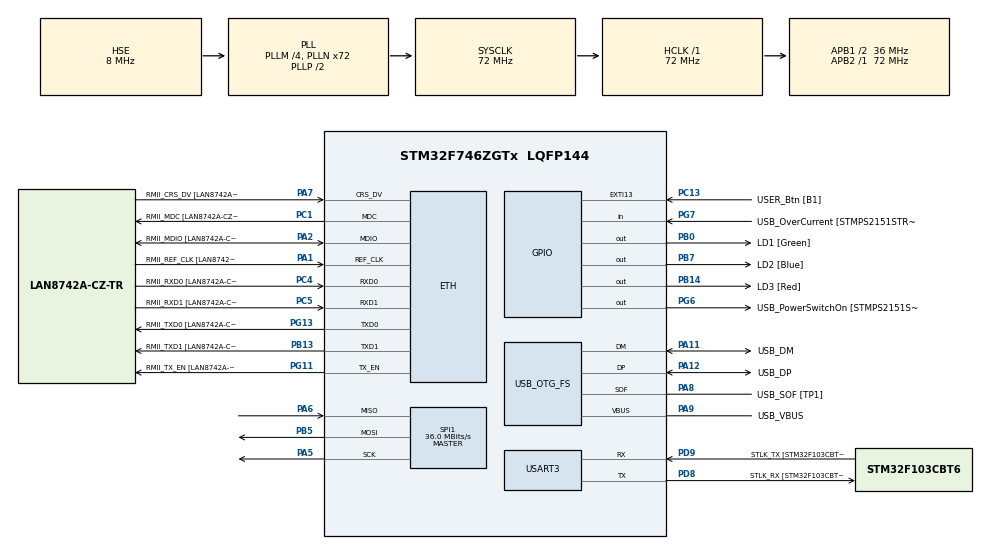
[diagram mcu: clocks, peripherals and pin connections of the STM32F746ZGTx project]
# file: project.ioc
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ETH.MediaInterface=ETH_MEDIA_INTERFACE_RMII
ETH.PHY_Name=LAN8742A_PHY_ADDRESS
ETH.PHY_Value=0
ETH.PhyAddress=0
FREERTOS.Tasks01=defaultTask,0,128,StartDefaultTask,Default,NULL
LWIP.Version=v2.0.3_Cube
Mcu.Family=STM32F7
Mcu.Name=STM32F746ZGTx
Mcu.Package=LQFP144
NVIC.ETH_IRQn=true\:5\:0\:false\:false\:true\:true\:false
NVIC.PriorityGroup=NVIC_PRIORITYGROUP_4
NVIC.TIM1_UP_TIM10_IRQn=true\:0\:0\:false\:false\:true\:false\:false
NVIC.TimeBase=TIM1_UP_TIM10_IRQn
NVIC.TimeBaseIP=TIM1
PA1.GPIO_Label=RMII_REF_CLK [LAN8742A-CZ-TR_REFCLK0]
PA1.Mode=RMII
PA1.Signal=ETH_REF_CLK
PA10.GPIO_Label=USB_ID
PA10.Signal=USB_OTG_FS_ID
PA11.GPIO_Label=USB_DM
PA11.Mode=Device_Only
PA11.Signal=USB_OTG_FS_DM
PA12.GPIO_Label=USB_DP
PA12.Mode=Device_Only
PA12.Signal=USB_OTG_FS_DP
PA13.GPIO_Label=TMS
PA13.Mode=Serial_Wire
PA13.Signal=SYS_JTMS-SWDIO
PA14.GPIO_Label=TCK
PA14.Mode=Serial_Wire
PA14.Signal=SYS_JTCK-SWCLK
PA2.GPIO_Label=RMII_MDIO [LAN8742A-CZ-TR_MDIO]
PA2.Mode=RMII
PA2.Signal=ETH_MDIO
PA5.Mode=Full_Duplex_Master
PA5.Signal=SPI1_SCK
PA6.Mode=Full_Duplex_Master
PA6.Signal=SPI1_MISO
PA7.GPIO_Label=RMII_CRS_DV [LAN8742A-CZ-TR_CRS_DV]
PA7.Mode=RMII
PA7.Signal=ETH_CRS_DV
PA8.GPIO_Label=USB_SOF [TP1]
PA8.Mode=Activate_SOF_FS
PA8.Signal=USB_OTG_FS_SOF
PA9.GPIO_Label=USB_VBUS
PA9.Mode=Activate_VBUS
PA9.Signal=USB_OTG_FS_VBUS
PB0.GPIO_Label=LD1 [Green]
PB0.Signal=GPIO_Output
PB13.GPIO_Label=RMII_TXD1 [LAN8742A-CZ-TR_TXD1]
PB13.Mode=RMII
PB13.Signal=ETH_TXD1
PB14.GPIO_Label=LD3 [Red]
PB14.Signal=GPIO_Output
PB3.GPIO_Label=SW0
PB3.Signal=SYS_JTDO-SWO
PB5.Mode=Full_Duplex_Master
PB5.Signal=SPI1_MOSI
PB7.GPIO_Label=LD2 [Blue]
PB7.Signal=GPIO_Output
PC1.GPIO_Label=RMII_MDC [LAN8742A-CZ-TR_MDC]
PC1.Mode=RMII
PC1.Signal=ETH_MDC
PC13.GPIO_Label=USER_Btn [B1]
PC13.Signal=GPXTI13
PC14/OSC32_IN.Mode=LSE-External-Oscillator
PC14/OSC32_IN.Signal=RCC_OSC32_IN
PC15/OSC32_OUT.Mode=LSE-External-Oscillator
PC15/OSC32_OUT.Signal=RCC_OSC32_OUT
PC4.GPIO_Label=RMII_RXD0 [LAN8742A-CZ-TR_RXD0]
PC4.Mode=RMII
PC4.Signal=ETH_RXD0
PC5.GPIO_Label=RMII_RXD1 [LAN8742A-CZ-TR_RXD1]
PC5.Mode=RMII
PC5.Signal=ETH_RXD1
PD8.GPIO_Label=STLK_RX [STM32F103CBT6_PA3]
PD8.Mode=Asynchronous
PD8.Signal=USART3_TX
PD9.GPIO_Label=STLK_TX [STM32F103CBT6_PA2]
PD9.Mode=Asynchronous
PD9.Signal=USART3_RX
PG11.GPIO_Label=RMII_TX_EN [LAN8742A-CZ-TR_TXEN]
PG11.Mode=RMII
PG11.Signal=ETH_TX_EN
PG13.GPIO_Label=RMII_TXD0 [LAN8742A-CZ-TR_TXD0]
PG13.Mode=RMII
PG13.Signal=ETH_TXD0
PG6.GPIO_Label=USB_PowerSwitchOn [STMPS2151STR_EN]
PG6.Signal=GPIO_Output
PG7.GPIO_Label=USB_OverCurrent [STMPS2151STR_FAULT]
PG7.Signal=GPIO_Input
PH0/OSC_IN.GPIO_Label=MCO [STM32F103CBT6_PA8]
PH0/OSC_IN.Mode=HSE-External-Clock-Source
PH0/OSC_IN.Signal=RCC_OSC_IN
PH1/OSC_OUT.Mode=HSE-External-Clock-Source
PH1/OSC_OUT.Signal=RCC_OSC_OUT
ProjectManager.HeapSize=0x200
ProjectManager.StackSize=0x400
ProjectManager.TargetToolchain=TrueSTUDIO
RCC.48MHZClocksFreq_Value=24000000
RCC.AHBFreq_Value=72000000
RCC.APB1CLKDivider=RCC_HCLK_DIV2
RCC.APB1Freq_Value=36000000
RCC.APB1TimFreq_Value=72000000
RCC.APB2Freq_Value=72000000
RCC.APB2TimFreq_Value=72000000
RCC.CortexFreq_Value=72000000
RCC.HCLKFreq_Value=72000000
RCC.HSE_VALUE=8000000
RCC.HSI_VALUE=16000000
RCC.PLLM=4
RCC.PLLMUL=RCC_PLL_MUL9
RCC.PLLN=72
RCC.PLLQ=3
RCC.PRESCALERUSB=RCC_USBCLKSOURCE_PLL_DIV1_5
RCC.SYSCLKFreq_VALUE=72000000
RCC.SYSCLKSource=RCC_SYSCLKSOURCE_PLLCLK
RCC.SYSCLKSourceVirtual=RCC_SYSCLKSOURCE_PLLCLK
RCC.USBFreq_Value=48000000
RCC.VCOOutputFreq_Value=144000000
SPI1.CalculateBaudRate=36.0 MBits/s
SPI1.Direction=SPI_DIRECTION_2LINES
SPI1.Mode=SPI_MODE_MASTER
SPI1.VirtualType=VM_MASTER
USART3.VirtualMode-Asynchronous=VM_ASYNC
USB_OTG_FS.VirtualMode=Device_Only
VP_FREERTOS_VS_ENABLE.Mode=Enabled
VP_LWIP_VS_Enabled.Mode=Enabled
VP_SYS_VS_tim1.Mode=TIM1
board=NUCLEO-F746ZG

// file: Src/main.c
/**
  ******************************************************************************
  * @file           : main.c
  * @brief          : Main program body
  ******************************************************************************
  * This notice applies to any and all portions of this file
  * that are not between comment pairs USER CODE BEGIN and
  * USER CODE END. Other portions of this file, whether
  * inserted by the user or by software development tools
  * are owned by their respective copyright owners.
  *
  * Copyright (c) 2018 STMicroelectronics International N.V.
  * All rights reserved.
  *
  * Redistribution and use in source and binary forms, with or without
  * modification, are permitted, provided that the following conditions are met:
  *
  * 1. Redistribution of source code must retain the above copyright notice,
  *    this list of conditions and the following disclaimer.
  * 2. Redistributions in binary form must reproduce the above copyright notice,
  *    this list of conditions and the following disclaimer in the documentation
  *    and/or other materials provided with the distribution.
  * 3. Neither the name of STMicroelectronics nor the names of other
  *    contributors to this software may be used to endorse or promote products
  *    derived from this software without specific written permission.
  * 4. This software, including modifications and/or derivative works of this
  *    software, must execute solely and exclusively on microcontroller or
  *    microprocessor devices manufactured by or for STMicroelectronics.
  * 5. Redistribution and use of this software other than as permitted under
  *    this license is void and will automatically terminate your rights under
  *    this license.
  *
  * THIS SOFTWARE IS PROVIDED BY STMICROELECTRONICS AND CONTRIBUTORS "AS IS"
  * AND ANY EXPRESS, IMPLIED OR STATUTORY WARRANTIES, INCLUDING, BUT NOT
  * LIMITED TO, THE IMPLIED WARRANTIES OF MERCHANTABILITY, FITNESS FOR A
  * PARTICULAR PURPOSE AND NON-INFRINGEMENT OF THIRD PARTY INTELLECTUAL PROPERTY
  * RIGHTS ARE DISCLAIMED TO THE FULLEST EXTENT PERMITTED BY LAW. IN NO EVENT
  * SHALL STMICROELECTRONICS OR CONTRIBUTORS BE LIABLE FOR ANY DIRECT, INDIRECT,
  * INCIDENTAL, SPECIAL, EXEMPLARY, OR CONSEQUENTIAL DAMAGES (INCLUDING, BUT NOT
  * LIMITED TO, PROCUREMENT OF SUBSTITUTE GOODS OR SERVICES; LOSS OF USE, DATA,
  * OR PROFITS; OR BUSINESS INTERRUPTION) HOWEVER CAUSED AND ON ANY THEORY OF
  * LIABILITY, WHETHER IN CONTRACT, STRICT LIABILITY, OR TORT (INCLUDING
  * NEGLIGENCE OR OTHERWISE) ARISING IN ANY WAY OUT OF THE USE OF THIS SOFTWARE,
  * EVEN IF ADVISED OF THE POSSIBILITY OF SUCH DAMAGE.
  *
  ******************************************************************************
  */
#include "main.h"
#include "stm32f7xx_hal.h"
#include "cmsis_os.h"
#include "lwip.h"

/* USER CODE BEGIN Includes */

#include "rfid-rc522.h"
#include "term_io.h"
#include "httpserver-netconn.h"
#include "tag_scanner.h"

/* USER CODE END Includes */

SPI_HandleTypeDef hspi1;
UART_HandleTypeDef huart3;
PCD_HandleTypeDef hpcd_USB_OTG_FS;
osThreadId defaultTaskHandle;

/* USER CODE BEGIN PV */
/* Private variables ---------------------------------------------------------*/
extern struct netif gnetif;
int privilage_status = 2;
int add_admin = 0;

/* USER CODE END PV */

void SystemClock_Config(void);
static void MX_GPIO_Init(void);
static void MX_USB_OTG_FS_PCD_Init(void);
static void MX_SPI1_Init(void);
static void MX_USART3_UART_Init(void);
void StartDefaultTask(void const * argument);

/* USER CODE BEGIN PFP */
/* Private function prototypes -----------------------------------------------*/

/* USER CODE END PFP */

int main(void)
{

  /* MCU Configuration----------------------------------------------------------*/

  /* Reset of all peripherals, Initializes the Flash interface and the Systick. */
  HAL_Init();

  /* Configure the system clock */
  SystemClock_Config();

  /* Initialize all configured peripherals */
  MX_GPIO_Init();
  MX_USB_OTG_FS_PCD_Init();
  MX_SPI1_Init();
  MX_USART3_UART_Init();

  /* USER CODE BEGIN 2 */
  RFID_RC522_Init();
  debug_init(&huart3);

  /* USER CODE END 2 */

  /* Create the thread(s) */
  /* definition and creation of defaultTask */
  osThreadDef(defaultTask, StartDefaultTask, osPriorityNormal, 0, 128);
  defaultTaskHandle = osThreadCreate(osThread(defaultTask), NULL);

  /* Start scheduler */
  osKernelStart();

  /* We should never get here as control is now taken by the scheduler */

  /* Infinite loop */
  while (1)
  {

  }

}

void SystemClock_Config(void)
{

  RCC_OscInitTypeDef RCC_OscInitStruct;
  RCC_ClkInitTypeDef RCC_ClkInitStruct;
  RCC_PeriphCLKInitTypeDef PeriphClkInitStruct;

    /**Configure the main internal regulator output voltage
    */
  __HAL_RCC_PWR_CLK_ENABLE();

  __HAL_PWR_VOLTAGESCALING_CONFIG(PWR_REGULATOR_VOLTAGE_SCALE3);

    /**Initializes the CPU, AHB and APB busses clocks
    */
  RCC_OscInitStruct.OscillatorType = RCC_OSCILLATORTYPE_HSE;
  RCC_OscInitStruct.HSEState = RCC_HSE_BYPASS;
  RCC_OscInitStruct.PLL.PLLState = RCC_PLL_ON;
  RCC_OscInitStruct.PLL.PLLSource = RCC_PLLSOURCE_HSE;
  RCC_OscInitStruct.PLL.PLLM = 4;
  RCC_OscInitStruct.PLL.PLLN = 72;
  RCC_OscInitStruct.PLL.PLLP = RCC_PLLP_DIV2;
  RCC_OscInitStruct.PLL.PLLQ = 3;
  if (HAL_RCC_OscConfig(&RCC_OscInitStruct) != HAL_OK)
  {
    _Error_Handler(__FILE__, __LINE__);
  }

    /**Initializes the CPU, AHB and APB busses clocks
    */
  RCC_ClkInitStruct.ClockType = RCC_CLOCKTYPE_HCLK|RCC_CLOCKTYPE_SYSCLK
                              |RCC_CLOCKTYPE_PCLK1|RCC_CLOCKTYPE_PCLK2;
  RCC_ClkInitStruct.SYSCLKSource = RCC_SYSCLKSOURCE_PLLCLK;
  RCC_ClkInitStruct.AHBCLKDivider = RCC_SYSCLK_DIV1;
  RCC_ClkInitStruct.APB1CLKDivider = RCC_HCLK_DIV2;
  RCC_ClkInitStruct.APB2CLKDivider = RCC_HCLK_DIV1;

  if (HAL_RCC_ClockConfig(&RCC_ClkInitStruct, FLASH_LATENCY_2) != HAL_OK)
  {
    _Error_Handler(__FILE__, __LINE__);
  }

  PeriphClkInitStruct.PeriphClockSelection = RCC_PERIPHCLK_USART3|RCC_PERIPHCLK_CLK48;
  PeriphClkInitStruct.Usart3ClockSelection = RCC_USART3CLKSOURCE_PCLK1;
  PeriphClkInitStruct.Clk48ClockSelection = RCC_CLK48SOURCE_PLL;
  if (HAL_RCCEx_PeriphCLKConfig(&PeriphClkInitStruct) != HAL_OK)
  {
    _Error_Handler(__FILE__, __LINE__);
  }

    /**Configure the Systick interrupt time
    */
  HAL_SYSTICK_Config(HAL_RCC_GetHCLKFreq()/1000);

    /**Configure the Systick
    */
  HAL_SYSTICK_CLKSourceConfig(SYSTICK_CLKSOURCE_HCLK);

  /* SysTick_IRQn interrupt configuration */
  HAL_NVIC_SetPriority(SysTick_IRQn, 15, 0);
}

/* SPI1 init function */
static void MX_SPI1_Init(void)
{

  /* SPI1 parameter configuration*/
  hspi1.Instance = SPI1;
  hspi1.Init.Mode = SPI_MODE_MASTER;
  hspi1.Init.Direction = SPI_DIRECTION_2LINES;
  hspi1.Init.DataSize = SPI_DATASIZE_8BIT;
  hspi1.Init.CLKPolarity = SPI_POLARITY_LOW;
  hspi1.Init.CLKPhase = SPI_PHASE_1EDGE;
  hspi1.Init.NSS = SPI_NSS_SOFT;
  hspi1.Init.BaudRatePrescaler = SPI_BAUDRATEPRESCALER_32;
  hspi1.Init.FirstBit = SPI_FIRSTBIT_MSB;
  hspi1.Init.TIMode = SPI_TIMODE_DISABLE;
  hspi1.Init.CRCCalculation = SPI_CRCCALCULATION_DISABLE;
  hspi1.Init.CRCPolynomial = 7;
  hspi1.Init.CRCLength = SPI_CRC_LENGTH_DATASIZE;
  hspi1.Init.NSSPMode = SPI_NSS_PULSE_ENABLE;
  if (HAL_SPI_Init(&hspi1) != HAL_OK)
  {
    _Error_Handler(__FILE__, __LINE__);
  }

}

/* USART3 init function */
static void MX_USART3_UART_Init(void)
{

  huart3.Instance = USART3;
  huart3.Init.BaudRate = 115200;
  huart3.Init.WordLength = UART_WORDLENGTH_8B;
  huart3.Init.StopBits = UART_STOPBITS_1;
  huart3.Init.Parity = UART_PARITY_NONE;
  huart3.Init.Mode = UART_MODE_TX_RX;
  huart3.Init.HwFlowCtl = UART_HWCONTROL_NONE;
  huart3.Init.OverSampling = UART_OVERSAMPLING_16;
  huart3.Init.OneBitSampling = UART_ONE_BIT_SAMPLE_DISABLE;
  huart3.AdvancedInit.AdvFeatureInit = UART_ADVFEATURE_NO_INIT;
  if (HAL_UART_Init(&huart3) != HAL_OK)
  {
    _Error_Handler(__FILE__, __LINE__);
  }

}

/* USB_OTG_FS init function */
static void MX_USB_OTG_FS_PCD_Init(void)
{

  hpcd_USB_OTG_FS.Instance = USB_OTG_FS;
  hpcd_USB_OTG_FS.Init.dev_endpoints = 6;
  hpcd_USB_OTG_FS.Init.speed = PCD_SPEED_FULL;
  hpcd_USB_OTG_FS.Init.dma_enable = DISABLE;
  hpcd_USB_OTG_FS.Init.ep0_mps = DEP0CTL_MPS_64;
  hpcd_USB_OTG_FS.Init.phy_itface = PCD_PHY_EMBEDDED;
  hpcd_USB_OTG_FS.Init.Sof_enable = ENABLE;
  hpcd_USB_OTG_FS.Init.low_power_enable = DISABLE;
  hpcd_USB_OTG_FS.Init.lpm_enable = DISABLE;
  hpcd_USB_OTG_FS.Init.vbus_sensing_enable = ENABLE;
  hpcd_USB_OTG_FS.Init.use_dedicated_ep1 = DISABLE;
  if (HAL_PCD_Init(&hpcd_USB_OTG_FS) != HAL_OK)
  {
    _Error_Handler(__FILE__, __LINE__);
  }

}

/** Configure pins as
        * Analog
        * Input
        * Output
        * EVENT_OUT
        * EXTI
*/
static void MX_GPIO_Init(void)
{

  GPIO_InitTypeDef GPIO_InitStruct;

  /* GPIO Ports Clock Enable */
  __HAL_RCC_GPIOC_CLK_ENABLE();
  __HAL_RCC_GPIOH_CLK_ENABLE();
  __HAL_RCC_GPIOA_CLK_ENABLE();
  __HAL_RCC_GPIOB_CLK_ENABLE();
  __HAL_RCC_GPIOD_CLK_ENABLE();
  __HAL_RCC_GPIOG_CLK_ENABLE();

  /*Configure GPIO pin Output Level */
  HAL_GPIO_WritePin(GPIOB, LD1_Pin|LD3_Pin|LD2_Pin, GPIO_PIN_RESET);

  /*Configure GPIO pin Output Level */
  HAL_GPIO_WritePin(GPIOD, GPIO_PIN_9, GPIO_PIN_RESET);

  /*Configure GPIO pin Output Level */
  HAL_GPIO_WritePin(GPIOD, SPI_CS_Pin|RFID_RST_Pin, GPIO_PIN_SET);

  /*Configure GPIO pin Output Level */
  HAL_GPIO_WritePin(USB_PowerSwitchOn_GPIO_Port, USB_PowerSwitchOn_Pin, GPIO_PIN_RESET);

  /*Configure GPIO pin : USER_Btn_Pin */
  GPIO_InitStruct.Pin = USER_Btn_Pin;
  GPIO_InitStruct.Mode = GPIO_MODE_IT_RISING;
  GPIO_InitStruct.Pull = GPIO_NOPULL;
  HAL_GPIO_Init(USER_Btn_GPIO_Port, &GPIO_InitStruct);

  /*Configure GPIO pins : LD1_Pin LD3_Pin LD2_Pin */
  GPIO_InitStruct.Pin = LD1_Pin|LD3_Pin|LD2_Pin;
  GPIO_InitStruct.Mode = GPIO_MODE_OUTPUT_PP;
  GPIO_InitStruct.Pull = GPIO_NOPULL;
  GPIO_InitStruct.Speed = GPIO_SPEED_FREQ_LOW;
  HAL_GPIO_Init(GPIOB, &GPIO_InitStruct);

  /*Configure GPIO pins : PD9 SPI_CS_Pin RFID_RST_Pin */
  GPIO_InitStruct.Pin = GPIO_PIN_9|SPI_CS_Pin|RFID_RST_Pin;
  GPIO_InitStruct.Mode = GPIO_MODE_OUTPUT_PP;
  GPIO_InitStruct.Pull = GPIO_NOPULL;
  GPIO_InitStruct.Speed = GPIO_SPEED_FREQ_LOW;
  HAL_GPIO_Init(GPIOD, &GPIO_InitStruct);

  /*Configure GPIO pin : USB_PowerSwitchOn_Pin */
  GPIO_InitStruct.Pin = USB_PowerSwitchOn_Pin;
  GPIO_InitStruct.Mode = GPIO_MODE_OUTPUT_PP;
  GPIO_InitStruct.Pull = GPIO_NOPULL;
  GPIO_InitStruct.Speed = GPIO_SPEED_FREQ_LOW;
  HAL_GPIO_Init(USB_PowerSwitchOn_GPIO_Port, &GPIO_InitStruct);

  /*Configure GPIO pin : USB_OverCurrent_Pin */
  GPIO_InitStruct.Pin = USB_OverCurrent_Pin;
  GPIO_InitStruct.Mode = GPIO_MODE_INPUT;
  GPIO_InitStruct.Pull = GPIO_NOPULL;
  HAL_GPIO_Init(USB_OverCurrent_GPIO_Port, &GPIO_InitStruct);

}

/* USER CODE BEGIN 4 */

//tmp
int check_tag_if_admin(char * CardID) {

	if(strcmp(CardID, "0xc48150d3") == 0)
		return 1;
	return 0;
}

/* USER CODE END 4 */

void StartDefaultTask(void const * argument)
{
  /* init code for LWIP */
  MX_LWIP_Init();

  /* USER CODE BEGIN 5 */

  xprintf("Start!! <3\n\r");

  while(gnetif.ip_addr.addr == 0)
  {
	  osDelay(1000);
	  xprintf("Waiting for ip...\n\r");
  }
  xprintf("Our ip address is: %u.%u.%u.%u\n\r\n\r",
		  ip4_addr1(&gnetif.ip_addr),
		  ip4_addr2(&gnetif.ip_addr),
		  ip4_addr3(&gnetif.ip_addr),
		  ip4_addr4(&gnetif.ip_addr));
  xprintf("Connect to: %u.%u.%u.%u:80/index.html\n\r\n\r",
  		  ip4_addr1(&gnetif.ip_addr),
  		  ip4_addr2(&gnetif.ip_addr),
  		  ip4_addr3(&gnetif.ip_addr),
  		  ip4_addr4(&gnetif.ip_addr));
  osDelay(1000);
  privilage_status = 2;
  http_server_netconn_init();
  tag_scanner_init();

  /* Infinite loop */
  for(;;)
  {
    osDelay(120000); // wait 2 minutes, then change privileges to other
    // TODO probably won't work since thread priority too small
    privilage_status = ADMIN_PRIVILAGE;
    xprintf("main looop\n\r");
  }
  /* USER CODE END 5 */
}

void HAL_TIM_PeriodElapsedCallback(TIM_HandleTypeDef *htim)
{
  if (htim->Instance == TIM1) {
    HAL_IncTick();
  }
}

void _Error_Handler(char *file, int line)
{
  while(1)
  {
  }
}

/************************ (C) COPYRIGHT STMicroelectronics *****END OF FILE****/
